VERSION 5.7 ;
  NOWIREEXTENSIONATPIN ON ;
  DIVIDERCHAR "/" ;
  BUSBITCHARS "[]" ;
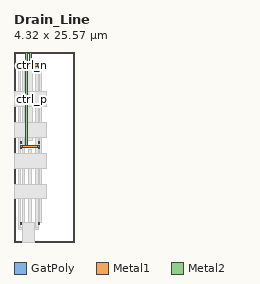
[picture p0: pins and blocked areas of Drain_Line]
MACRO Drain_Line
  CLASS BLOCK ;
  FOREIGN Drain_Line ;
  ORIGIN 0.000 0.000 ;
  SIZE 4.320 BY 25.570 ;
  PIN ctrl_p
    ANTENNAGATEAREA 2.600000 ;
    PORT
      LAYER GatPoly ;
        RECT 0.835 12.750 1.135 13.050 ;
        RECT 3.185 12.750 3.485 13.050 ;
        RECT 0.920 12.570 1.050 12.750 ;
        RECT 3.270 12.570 3.400 12.750 ;
        RECT 0.920 2.390 1.050 2.570 ;
        RECT 3.270 2.390 3.400 2.570 ;
      LAYER Metal1 ;
        RECT 0.835 12.750 3.485 13.050 ;
      LAYER Metal2 ;
        RECT 1.610 12.755 1.810 25.570 ;
    END
  END ctrl_p
  PIN ctrl_n
    ANTENNAGATEAREA 2.600000 ;
    PORT
      LAYER GatPoly ;
        RECT 0.835 23.660 1.135 23.960 ;
        RECT 3.185 23.660 3.485 23.960 ;
        RECT 0.920 23.480 1.050 23.660 ;
        RECT 3.270 23.480 3.400 23.660 ;
        RECT 0.920 13.300 1.050 13.480 ;
        RECT 3.270 13.300 3.400 13.480 ;
      LAYER Metal1 ;
        RECT 0.835 23.660 3.485 23.960 ;
      LAYER Metal2 ;
        RECT 2.090 23.665 2.290 25.570 ;
    END
  END ctrl_n
  OBS
      LAYER Metal1 ;
        RECT 0.580 13.480 0.880 23.480 ;
        RECT 1.090 13.480 1.390 23.480 ;
        RECT 1.860 13.640 2.460 23.320 ;
        RECT 2.930 13.480 3.230 23.480 ;
        RECT 3.440 13.480 3.740 23.480 ;
        RECT 0.580 2.570 0.880 12.570 ;
        RECT 1.090 2.570 1.390 12.570 ;
        RECT 1.910 2.690 2.410 12.470 ;
        RECT 2.930 2.570 3.230 12.570 ;
        RECT 3.440 2.570 3.740 12.570 ;
      LAYER Metal2 ;
        RECT 0.580 1.970 0.880 23.480 ;
        RECT 1.090 13.480 1.390 23.480 ;
        RECT 2.020 19.095 2.400 19.475 ;
        RECT 1.090 2.570 1.390 12.570 ;
        RECT 2.020 6.605 2.400 6.985 ;
        RECT 2.930 1.970 3.230 23.480 ;
        RECT 3.440 13.480 3.740 23.480 ;
        RECT 3.440 2.570 3.740 12.570 ;
        RECT 0.580 1.670 3.230 1.970 ;
      LAYER Metal3 ;
        RECT 1.090 2.570 1.390 23.480 ;
        RECT 1.910 18.985 2.510 19.585 ;
        RECT 1.910 6.495 2.510 7.095 ;
        RECT 3.440 2.570 3.740 23.480 ;
        RECT 1.605 1.520 2.205 2.120 ;
      LAYER Metal4 ;
        RECT 1.910 18.985 2.510 19.585 ;
        RECT 0.945 14.815 1.545 15.415 ;
        RECT 2.775 10.655 3.895 11.255 ;
        RECT 1.910 6.495 2.510 7.095 ;
        RECT 1.605 1.520 2.205 2.120 ;
      LAYER Metal5 ;
        RECT 1.390 18.465 3.030 20.105 ;
        RECT 0.425 14.295 2.065 15.935 ;
        RECT 2.265 10.135 3.905 11.775 ;
        RECT 1.390 5.975 3.030 7.615 ;
        RECT 1.085 1.000 2.725 2.640 ;
      LAYER TopMetal1 ;
        RECT 1.260 18.335 3.160 20.235 ;
        RECT 0.295 14.165 2.195 16.065 ;
        RECT 2.135 10.005 4.035 11.905 ;
        RECT 1.260 5.845 3.160 7.745 ;
        RECT 1.085 0.000 2.725 2.640 ;
      LAYER TopMetal2 ;
        RECT 0.000 18.285 4.320 20.285 ;
        RECT 0.000 14.115 4.320 16.115 ;
        RECT 0.000 9.955 4.320 11.955 ;
        RECT 0.000 5.795 4.320 7.795 ;
  END
END Drain_Line
END LIBRARY

